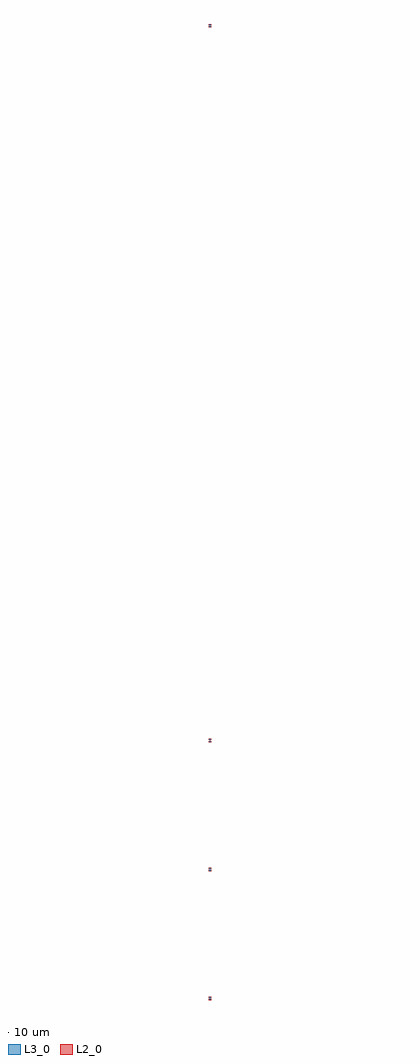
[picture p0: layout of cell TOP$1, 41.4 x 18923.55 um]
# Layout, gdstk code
import gdstk
lib = gdstk.Library(unit=1e-6, precision=1e-09)
def P(c, l, *ps):  # polygons
    for p in ps: c.add(gdstk.Polygon(p, *l))
L2_0 = (2, 0)
L3_0 = (3, 0)

q16gap = lib.new_cell('Q16GAP')
P(q16gap, L2_0, [(779.3,2253.3),(779.3,2274),(798.96,2284),(799.46,2284),(799.46,2286),(799.66,2286),(799.66,2284),(780,2274),(780,2254),(820,2254),(820,2274),(800.34,2284),(800.34,2286),(797.3,2286),(797.3,2286.15),(796.8,2286.15),(779.3,2296.15),(779.3,2316.15),(780,2316.15),(780,2296.15),(797.5,2286.15),(802.5,2286.15),(820,2296.15),(820,2316.15),(779.3,2316.15),(779.3,2316.85),(820.7,2316.85),(820.7,2296.15),(803.2,2286.15),(802.7,2286.15),(802.7,2286),(800.54,2286),(800.54,2284),(801.04,2284),(820.7,2274),(820.7,2253.3)],
  [(779.3,4753.3),(779.3,4774),(798.96,4784),(799.46,4784),(799.46,4786),(799.66,4786),(799.66,4784),(780,4774),(780,4754),(820,4754),(820,4774),(800.34,4784),(800.34,4786),(797.3,4786),(797.3,4786.15),(796.8,4786.15),(779.3,4796.15),(779.3,4816.15),(780,4816.15),(780,4796.15),(797.5,4786.15),(802.5,4786.15),(820,4796.15),(820,4816.15),(779.3,4816.15),(779.3,4816.85),(820.7,4816.85),(820.7,4796.15),(803.2,4786.15),(802.7,4786.15),(802.7,4786),(800.54,4786),(800.54,4784),(801.04,4784),(820.7,4774),(820.7,4753.3)],
  [(779.3,7253.3),(779.3,7274),(798.96,7284),(799.46,7284),(799.46,7286),(799.66,7286),(799.66,7284),(780,7274),(780,7254),(820,7254),(820,7274),(800.34,7284),(800.34,7286),(797.3,7286),(797.3,7286.15),(796.8,7286.15),(779.3,7296.15),(779.3,7316.15),(780,7316.15),(780,7296.15),(797.5,7286.15),(802.5,7286.15),(820,7296.15),(820,7316.15),(779.3,7316.15),(779.3,7316.85),(820.7,7316.85),(820.7,7296.15),(803.2,7286.15),(802.7,7286.15),(802.7,7286),(800.54,7286),(800.54,7284),(801.04,7284),(820.7,7274),(820.7,7253.3)],
  [(779.3,21113.3),(779.3,21134),(798.96,21144),(799.46,21144),(799.46,21146),(799.66,21146),(799.66,21144),(780,21134),(780,21114),(820,21114),(820,21134),(800.34,21144),(800.34,21146),(797.3,21146),(797.3,21146.15),(796.8,21146.15),(779.3,21156.15),(779.3,21176.15),(780,21176.15),(780,21156.15),(797.5,21146.15),(802.5,21146.15),(820,21156.15),(820,21176.15),(779.3,21176.15),(779.3,21176.85),(820.7,21176.85),(820.7,21156.15),(803.2,21146.15),(802.7,21146.15),(802.7,21146),(800.54,21146),(800.54,21144),(801.04,21144),(820.7,21134),(820.7,21113.3)])

q16pin = lib.new_cell('Q16PIN')
P(q16pin, L3_0, [(780,2254),(780,2274),(799.66,2284),(799.66,2286),(800.34,2286),(800.34,2284),(820,2274),(820,2254)],
  [(797.5,2286.15),(780,2296.15),(780,2316.15),(820,2316.15),(820,2296.15),(802.5,2286.15)],
  [(780,4754),(780,4774),(799.66,4784),(799.66,4786),(800.34,4786),(800.34,4784),(820,4774),(820,4754)],
  [(797.5,4786.15),(780,4796.15),(780,4816.15),(820,4816.15),(820,4796.15),(802.5,4786.15)],
  [(780,7254),(780,7274),(799.66,7284),(799.66,7286),(800.34,7286),(800.34,7284),(820,7274),(820,7254)],
  [(797.5,7286.15),(780,7296.15),(780,7316.15),(820,7316.15),(820,7296.15),(802.5,7286.15)],
  [(780,21114),(780,21134),(799.66,21144),(799.66,21146),(800.34,21146),(800.34,21144),(820,21134),(820,21114)],
  [(797.5,21146.15),(780,21156.15),(780,21176.15),(820,21176.15),(820,21156.15),(802.5,21146.15)])

q16 = lib.new_cell('Q16')

top_1 = lib.new_cell('TOP$1')
top_1.add(gdstk.Reference(q16gap, (0,0)))
top_1.add(gdstk.Reference(q16pin, (0,0)))
top_1.add(gdstk.Reference(q16, (0,0)))

lib.write_gds('TOP_1.gds')
